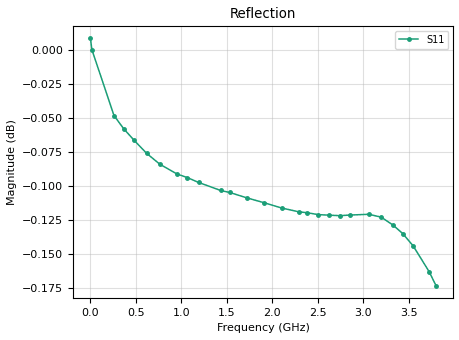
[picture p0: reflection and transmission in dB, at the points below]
! ListType=Lin
!!SAA-2 female short 0.1 to 3800MHz 500 points
# MHz S RI R 50
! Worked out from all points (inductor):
!   500 points, 100 kHz to 3.8 GHz, reference 50 ohm
!   read as one part to ground: L = 2.58 nH near 15.33 MHz
!   highest Q = 71.6 at 2.627 GHz (marker M1), where L = 2.87 nH
!   S11 on the Smith chart (normalised r, x): 100 kHz: -0.00, +0.00; 761.6 MHz: 0.01, +0.23; 1.531 GHz: 0.01, +0.47; 2.292 GHz: 0.01, +0.78; 3.061 GHz: 0.02, +1.22; 3.8 GHz: 0.05, +1.98
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0.1  -1.001 0.00118
15.33006  -1 0.0103
259.011  -0.9828 0.1519
365.6214  -0.9705 0.2119
479.8469  -0.9535 0.2751
616.9174  -0.9278 0.3491
761.603  -0.8948 0.4245
951.9788  -0.8426 0.5189
1066.204  -0.8067 0.5726
1188.045  -0.7645 0.6272
1431.726  -0.6692 0.7271
1530.721  -0.6266 0.7639
1721.097  -0.539 0.8275
1903.858  -0.4487 0.8793
2101.848  -0.3451 0.9244
2292.224  -0.2414 0.9564
2375.989  -0.1948 0.9669
2505.445  -0.1219 0.9786
2627.285  -0.0528 0.9847
2741.511  0.0122 0.986
2855.736  0.0772 0.9831
3061.342  0.1931 0.9671
3198.413  0.2695 0.9484
3327.868  0.3407 0.9245
3434.479  0.3981 0.9005
3548.704  0.4582 0.8703
3723.85  0.5463 0.8153
3800  0.5829 0.7881
